VERSION 5.7 ;
  NOWIREEXTENSIONATPIN ON ;
  DIVIDERCHAR "/" ;
  BUSBITCHARS "[]" ;
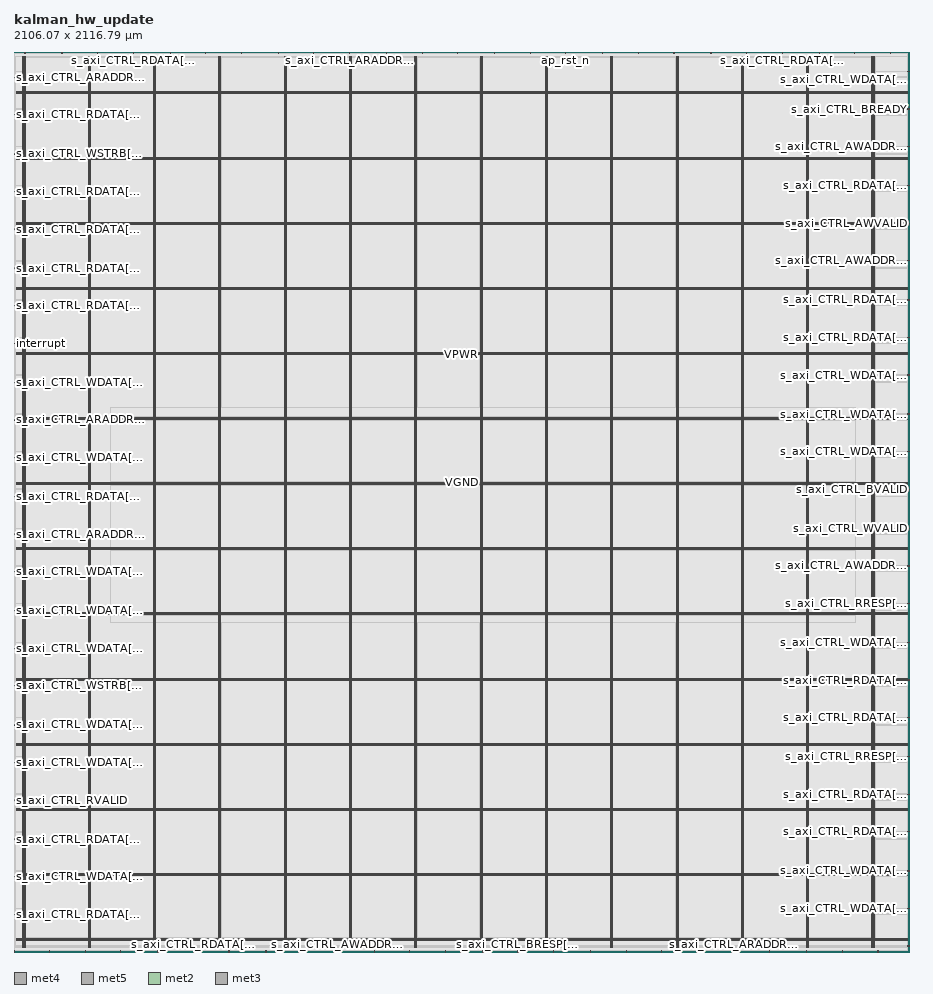
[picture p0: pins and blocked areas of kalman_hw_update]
MACRO kalman_hw_update
  CLASS BLOCK ;
  FOREIGN kalman_hw_update ;
  ORIGIN 0.000 0.000 ;
  SIZE 2106.070 BY 2116.790 ;
  PIN VGND
    DIRECTION INOUT ;
    USE GROUND ;
    PORT
      LAYER met4 ;
        RECT 24.340 10.640 25.940 2105.520 ;
    END
    PORT
      LAYER met4 ;
        RECT 177.940 10.640 179.540 2105.520 ;
    END
    PORT
      LAYER met4 ;
        RECT 331.540 10.640 333.140 2105.520 ;
    END
    PORT
      LAYER met4 ;
        RECT 485.140 10.640 486.740 2105.520 ;
    END
    PORT
      LAYER met4 ;
        RECT 638.740 10.640 640.340 2105.520 ;
    END
    PORT
      LAYER met4 ;
        RECT 792.340 10.640 793.940 2105.520 ;
    END
    PORT
      LAYER met4 ;
        RECT 945.940 10.640 947.540 2105.520 ;
    END
    PORT
      LAYER met4 ;
        RECT 1099.540 10.640 1101.140 2105.520 ;
    END
    PORT
      LAYER met4 ;
        RECT 1253.140 10.640 1254.740 2105.520 ;
    END
    PORT
      LAYER met4 ;
        RECT 1406.740 10.640 1408.340 2105.520 ;
    END
    PORT
      LAYER met4 ;
        RECT 1560.340 10.640 1561.940 2105.520 ;
    END
    PORT
      LAYER met4 ;
        RECT 1713.940 10.640 1715.540 2105.520 ;
    END
    PORT
      LAYER met4 ;
        RECT 1867.540 10.640 1869.140 2105.520 ;
    END
    PORT
      LAYER met4 ;
        RECT 2021.140 10.640 2022.740 2105.520 ;
    END
    PORT
      LAYER met5 ;
        RECT 5.280 30.030 2100.600 31.630 ;
    END
    PORT
      LAYER met5 ;
        RECT 5.280 183.210 2100.600 184.810 ;
    END
    PORT
      LAYER met5 ;
        RECT 5.280 336.390 2100.600 337.990 ;
    END
    PORT
      LAYER met5 ;
        RECT 5.280 489.570 2100.600 491.170 ;
    END
    PORT
      LAYER met5 ;
        RECT 5.280 642.750 2100.600 644.350 ;
    END
    PORT
      LAYER met5 ;
        RECT 5.280 795.930 2100.600 797.530 ;
    END
    PORT
      LAYER met5 ;
        RECT 5.280 949.110 2100.600 950.710 ;
    END
    PORT
      LAYER met5 ;
        RECT 5.280 1102.290 2100.600 1103.890 ;
    END
    PORT
      LAYER met5 ;
        RECT 5.280 1255.470 2100.600 1257.070 ;
    END
    PORT
      LAYER met5 ;
        RECT 5.280 1408.650 2100.600 1410.250 ;
    END
    PORT
      LAYER met5 ;
        RECT 5.280 1561.830 2100.600 1563.430 ;
    END
    PORT
      LAYER met5 ;
        RECT 5.280 1715.010 2100.600 1716.610 ;
    END
    PORT
      LAYER met5 ;
        RECT 5.280 1868.190 2100.600 1869.790 ;
    END
    PORT
      LAYER met5 ;
        RECT 5.280 2021.370 2100.600 2022.970 ;
    END
  END VGND
  PIN VPWR
    DIRECTION INOUT ;
    USE POWER ;
    PORT
      LAYER met4 ;
        RECT 21.040 10.640 22.640 2105.520 ;
    END
    PORT
      LAYER met4 ;
        RECT 174.640 10.640 176.240 2105.520 ;
    END
    PORT
      LAYER met4 ;
        RECT 328.240 10.640 329.840 2105.520 ;
    END
    PORT
      LAYER met4 ;
        RECT 481.840 10.640 483.440 2105.520 ;
    END
    PORT
      LAYER met4 ;
        RECT 635.440 10.640 637.040 2105.520 ;
    END
    PORT
      LAYER met4 ;
        RECT 789.040 10.640 790.640 2105.520 ;
    END
    PORT
      LAYER met4 ;
        RECT 942.640 10.640 944.240 2105.520 ;
    END
    PORT
      LAYER met4 ;
        RECT 1096.240 10.640 1097.840 2105.520 ;
    END
    PORT
      LAYER met4 ;
        RECT 1249.840 10.640 1251.440 2105.520 ;
    END
    PORT
      LAYER met4 ;
        RECT 1403.440 10.640 1405.040 2105.520 ;
    END
    PORT
      LAYER met4 ;
        RECT 1557.040 10.640 1558.640 2105.520 ;
    END
    PORT
      LAYER met4 ;
        RECT 1710.640 10.640 1712.240 2105.520 ;
    END
    PORT
      LAYER met4 ;
        RECT 1864.240 10.640 1865.840 2105.520 ;
    END
    PORT
      LAYER met4 ;
        RECT 2017.840 10.640 2019.440 2105.520 ;
    END
    PORT
      LAYER met5 ;
        RECT 5.280 26.730 2100.600 28.330 ;
    END
    PORT
      LAYER met5 ;
        RECT 5.280 179.910 2100.600 181.510 ;
    END
    PORT
      LAYER met5 ;
        RECT 5.280 333.090 2100.600 334.690 ;
    END
    PORT
      LAYER met5 ;
        RECT 5.280 486.270 2100.600 487.870 ;
    END
    PORT
      LAYER met5 ;
        RECT 5.280 639.450 2100.600 641.050 ;
    END
    PORT
      LAYER met5 ;
        RECT 5.280 792.630 2100.600 794.230 ;
    END
    PORT
      LAYER met5 ;
        RECT 5.280 945.810 2100.600 947.410 ;
    END
    PORT
      LAYER met5 ;
        RECT 5.280 1098.990 2100.600 1100.590 ;
    END
    PORT
      LAYER met5 ;
        RECT 5.280 1252.170 2100.600 1253.770 ;
    END
    PORT
      LAYER met5 ;
        RECT 5.280 1405.350 2100.600 1406.950 ;
    END
    PORT
      LAYER met5 ;
        RECT 5.280 1558.530 2100.600 1560.130 ;
    END
    PORT
      LAYER met5 ;
        RECT 5.280 1711.710 2100.600 1713.310 ;
    END
    PORT
      LAYER met5 ;
        RECT 5.280 1864.890 2100.600 1866.490 ;
    END
    PORT
      LAYER met5 ;
        RECT 5.280 2018.070 2100.600 2019.670 ;
    END
  END VPWR
  PIN ap_clk
    DIRECTION INPUT ;
    USE SIGNAL ;
    ANTENNAGATEAREA 1.286700 ;
    ANTENNADIFFAREA 0.434700 ;
    PORT
      LAYER met2 ;
        RECT 875.930 2112.790 876.210 2116.790 ;
    END
  END ap_clk
  PIN ap_rst_n
    DIRECTION INPUT ;
    USE SIGNAL ;
    ANTENNAGATEAREA 0.126000 ;
    PORT
      LAYER met2 ;
        RECT 1297.750 2112.790 1298.030 2116.790 ;
    END
  END ap_rst_n
  PIN interrupt
    DIRECTION OUTPUT TRISTATE ;
    USE SIGNAL ;
    ANTENNADIFFAREA 0.795200 ;
    PORT
      LAYER met3 ;
        RECT 0.000 1431.440 4.000 1432.040 ;
    END
  END interrupt
  PIN s_axi_CTRL_ARADDR[0]
    DIRECTION INPUT ;
    USE SIGNAL ;
    ANTENNAGATEAREA 0.126000 ;
    PORT
      LAYER met3 ;
        RECT 0.000 2057.040 4.000 2057.640 ;
    END
  END s_axi_CTRL_ARADDR[0]
  PIN s_axi_CTRL_ARADDR[1]
    DIRECTION INPUT ;
    USE SIGNAL ;
    ANTENNAGATEAREA 0.990000 ;
    PORT
      LAYER met2 ;
        RECT 1693.810 0.000 1694.090 4.000 ;
    END
  END s_axi_CTRL_ARADDR[1]
  PIN s_axi_CTRL_ARADDR[2]
    DIRECTION INPUT ;
    USE SIGNAL ;
    ANTENNAGATEAREA 0.126000 ;
    PORT
      LAYER met2 ;
        RECT 505.630 0.000 505.910 4.000 ;
    END
  END s_axi_CTRL_ARADDR[2]
  PIN s_axi_CTRL_ARADDR[3]
    DIRECTION INPUT ;
    USE SIGNAL ;
    ANTENNAGATEAREA 0.126000 ;
    PORT
      LAYER met2 ;
        RECT 788.990 2112.790 789.270 2116.790 ;
    END
  END s_axi_CTRL_ARADDR[3]
  PIN s_axi_CTRL_ARADDR[4]
    DIRECTION INPUT ;
    USE SIGNAL ;
    ANTENNAGATEAREA 0.126000 ;
    PORT
      LAYER met3 ;
        RECT 0.000 1251.240 4.000 1251.840 ;
    END
  END s_axi_CTRL_ARADDR[4]
  PIN s_axi_CTRL_ARADDR[5]
    DIRECTION INPUT ;
    USE SIGNAL ;
    ANTENNAGATEAREA 0.126000 ;
    PORT
      LAYER met3 ;
        RECT 0.000 982.640 4.000 983.240 ;
    END
  END s_axi_CTRL_ARADDR[5]
  PIN s_axi_CTRL_ARREADY
    DIRECTION OUTPUT TRISTATE ;
    USE SIGNAL ;
    ANTENNADIFFAREA 0.795200 ;
    PORT
      LAYER met2 ;
        RECT 251.250 0.000 251.530 4.000 ;
    END
  END s_axi_CTRL_ARREADY
  PIN s_axi_CTRL_ARVALID
    DIRECTION INPUT ;
    USE SIGNAL ;
    ANTENNAGATEAREA 0.126000 ;
    PORT
      LAYER met3 ;
        RECT 2102.070 13.640 2106.070 14.240 ;
    END
  END s_axi_CTRL_ARVALID
  PIN s_axi_CTRL_AWADDR[0]
    DIRECTION INPUT ;
    USE SIGNAL ;
    ANTENNAGATEAREA 0.126000 ;
    PORT
      LAYER met3 ;
        RECT 2102.070 1625.240 2106.070 1625.840 ;
    END
  END s_axi_CTRL_AWADDR[0]
  PIN s_axi_CTRL_AWADDR[1]
    DIRECTION INPUT ;
    USE SIGNAL ;
    ANTENNAGATEAREA 0.126000 ;
    PORT
      LAYER met2 ;
        RECT 1948.190 0.000 1948.470 4.000 ;
    END
  END s_axi_CTRL_AWADDR[1]
  PIN s_axi_CTRL_AWADDR[2]
    DIRECTION INPUT ;
    USE SIGNAL ;
    ANTENNAGATEAREA 0.126000 ;
    PORT
      LAYER met2 ;
        RECT 2060.890 2112.790 2061.170 2116.790 ;
    END
  END s_axi_CTRL_AWADDR[2]
  PIN s_axi_CTRL_AWADDR[3]
    DIRECTION INPUT ;
    USE SIGNAL ;
    ANTENNAGATEAREA 0.126000 ;
    PORT
      LAYER met3 ;
        RECT 2102.070 907.840 2106.070 908.440 ;
    END
  END s_axi_CTRL_AWADDR[3]
  PIN s_axi_CTRL_AWADDR[4]
    DIRECTION INPUT ;
    USE SIGNAL ;
    ANTENNAGATEAREA 0.126000 ;
    PORT
      LAYER met2 ;
        RECT 760.010 0.000 760.290 4.000 ;
    END
  END s_axi_CTRL_AWADDR[4]
  PIN s_axi_CTRL_AWADDR[5]
    DIRECTION INPUT ;
    USE SIGNAL ;
    ANTENNAGATEAREA 0.126000 ;
    PORT
      LAYER met3 ;
        RECT 2102.070 1893.840 2106.070 1894.440 ;
    END
  END s_axi_CTRL_AWADDR[5]
  PIN s_axi_CTRL_AWREADY
    DIRECTION OUTPUT TRISTATE ;
    USE SIGNAL ;
    ANTENNADIFFAREA 0.795200 ;
    PORT
      LAYER met2 ;
        RECT 621.550 2112.790 621.830 2116.790 ;
    END
  END s_axi_CTRL_AWREADY
  PIN s_axi_CTRL_AWVALID
    DIRECTION INPUT ;
    USE SIGNAL ;
    ANTENNAGATEAREA 0.126000 ;
    PORT
      LAYER met3 ;
        RECT 2102.070 1713.640 2106.070 1714.240 ;
    END
  END s_axi_CTRL_AWVALID
  PIN s_axi_CTRL_BREADY
    DIRECTION INPUT ;
    USE SIGNAL ;
    ANTENNAGATEAREA 0.126000 ;
    PORT
      LAYER met3 ;
        RECT 2102.070 1982.240 2106.070 1982.840 ;
    END
  END s_axi_CTRL_BREADY
  PIN s_axi_CTRL_BRESP[0]
    DIRECTION OUTPUT TRISTATE ;
    USE SIGNAL ;
    PORT
      LAYER met2 ;
        RECT 1185.050 0.000 1185.330 4.000 ;
    END
  END s_axi_CTRL_BRESP[0]
  PIN s_axi_CTRL_BRESP[1]
    DIRECTION OUTPUT TRISTATE ;
    USE SIGNAL ;
    PORT
      LAYER met2 ;
        RECT 1468.410 2112.790 1468.690 2116.790 ;
    END
  END s_axi_CTRL_BRESP[1]
  PIN s_axi_CTRL_BVALID
    DIRECTION OUTPUT TRISTATE ;
    USE SIGNAL ;
    ANTENNADIFFAREA 0.445500 ;
    PORT
      LAYER met3 ;
        RECT 2102.070 1088.040 2106.070 1088.640 ;
    END
  END s_axi_CTRL_BVALID
  PIN s_axi_CTRL_RDATA[0]
    DIRECTION OUTPUT TRISTATE ;
    USE SIGNAL ;
    ANTENNADIFFAREA 0.795200 ;
    PORT
      LAYER met3 ;
        RECT 2102.070 550.840 2106.070 551.440 ;
    END
  END s_axi_CTRL_RDATA[0]
  PIN s_axi_CTRL_RDATA[10]
    DIRECTION OUTPUT TRISTATE ;
    USE SIGNAL ;
    ANTENNADIFFAREA 0.795200 ;
    PORT
      LAYER met3 ;
        RECT 0.000 265.240 4.000 265.840 ;
    END
  END s_axi_CTRL_RDATA[10]
  PIN s_axi_CTRL_RDATA[11]
    DIRECTION OUTPUT TRISTATE ;
    USE SIGNAL ;
    ANTENNADIFFAREA 0.795200 ;
    PORT
      LAYER met2 ;
        RECT 846.950 0.000 847.230 4.000 ;
    END
  END s_axi_CTRL_RDATA[11]
  PIN s_axi_CTRL_RDATA[12]
    DIRECTION OUTPUT TRISTATE ;
    USE SIGNAL ;
    ANTENNADIFFAREA 0.795200 ;
    PORT
      LAYER met2 ;
        RECT 1777.530 0.000 1777.810 4.000 ;
    END
  END s_axi_CTRL_RDATA[12]
  PIN s_axi_CTRL_RDATA[13]
    DIRECTION OUTPUT TRISTATE ;
    USE SIGNAL ;
    ANTENNADIFFAREA 0.795200 ;
    PORT
      LAYER met2 ;
        RECT 959.650 2112.790 959.930 2116.790 ;
    END
  END s_axi_CTRL_RDATA[13]
  PIN s_axi_CTRL_RDATA[14]
    DIRECTION OUTPUT TRISTATE ;
    USE SIGNAL ;
    ANTENNADIFFAREA 0.795200 ;
    PORT
      LAYER met2 ;
        RECT 1384.690 2112.790 1384.970 2116.790 ;
    END
  END s_axi_CTRL_RDATA[14]
  PIN s_axi_CTRL_RDATA[15]
    DIRECTION OUTPUT TRISTATE ;
    USE SIGNAL ;
    ANTENNADIFFAREA 0.445500 ;
    PORT
      LAYER met3 ;
        RECT 2102.070 1802.040 2106.070 1802.640 ;
    END
  END s_axi_CTRL_RDATA[15]
  PIN s_axi_CTRL_RDATA[16]
    DIRECTION OUTPUT TRISTATE ;
    USE SIGNAL ;
    ANTENNADIFFAREA 0.445500 ;
    PORT
      LAYER met3 ;
        RECT 2102.070 370.640 2106.070 371.240 ;
    END
  END s_axi_CTRL_RDATA[16]
  PIN s_axi_CTRL_RDATA[17]
    DIRECTION OUTPUT TRISTATE ;
    USE SIGNAL ;
    ANTENNADIFFAREA 0.795200 ;
    PORT
      LAYER met2 ;
        RECT 1043.370 2112.790 1043.650 2116.790 ;
    END
  END s_axi_CTRL_RDATA[17]
  PIN s_axi_CTRL_RDATA[18]
    DIRECTION OUTPUT TRISTATE ;
    USE SIGNAL ;
    ANTENNADIFFAREA 0.795200 ;
    PORT
      LAYER met2 ;
        RECT 25.850 2112.790 26.130 2116.790 ;
    END
  END s_axi_CTRL_RDATA[18]
  PIN s_axi_CTRL_RDATA[19]
    DIRECTION OUTPUT TRISTATE ;
    USE SIGNAL ;
    ANTENNADIFFAREA 0.795200 ;
    PORT
      LAYER met2 ;
        RECT 1806.510 2112.790 1806.790 2116.790 ;
    END
  END s_axi_CTRL_RDATA[19]
  PIN s_axi_CTRL_RDATA[1]
    DIRECTION OUTPUT TRISTATE ;
    USE SIGNAL ;
    ANTENNADIFFAREA 0.795200 ;
    PORT
      LAYER met2 ;
        RECT 421.910 0.000 422.190 4.000 ;
    END
  END s_axi_CTRL_RDATA[1]
  PIN s_axi_CTRL_RDATA[20]
    DIRECTION OUTPUT TRISTATE ;
    USE SIGNAL ;
    ANTENNADIFFAREA 0.795200 ;
    PORT
      LAYER met2 ;
        RECT 705.270 2112.790 705.550 2116.790 ;
    END
  END s_axi_CTRL_RDATA[20]
  PIN s_axi_CTRL_RDATA[21]
    DIRECTION OUTPUT TRISTATE ;
    USE SIGNAL ;
    ANTENNADIFFAREA 0.445500 ;
    PORT
      LAYER met3 ;
        RECT 2102.070 1533.440 2106.070 1534.040 ;
    END
  END s_axi_CTRL_RDATA[21]
  PIN s_axi_CTRL_RDATA[22]
    DIRECTION OUTPUT TRISTATE ;
    USE SIGNAL ;
    ANTENNADIFFAREA 0.445500 ;
    PORT
      LAYER met3 ;
        RECT 2102.070 639.240 2106.070 639.840 ;
    END
  END s_axi_CTRL_RDATA[22]
  PIN s_axi_CTRL_RDATA[23]
    DIRECTION OUTPUT TRISTATE ;
    USE SIGNAL ;
    ANTENNADIFFAREA 0.795200 ;
    PORT
      LAYER met2 ;
        RECT 1214.030 2112.790 1214.310 2116.790 ;
    END
  END s_axi_CTRL_RDATA[23]
  PIN s_axi_CTRL_RDATA[24]
    DIRECTION OUTPUT TRISTATE ;
    USE SIGNAL ;
    ANTENNADIFFAREA 0.795200 ;
    PORT
      LAYER met2 ;
        RECT 1893.450 2112.790 1893.730 2116.790 ;
    END
  END s_axi_CTRL_RDATA[24]
  PIN s_axi_CTRL_RDATA[25]
    DIRECTION OUTPUT TRISTATE ;
    USE SIGNAL ;
    ANTENNADIFFAREA 0.795200 ;
    PORT
      LAYER met2 ;
        RECT 2031.910 0.000 2032.190 4.000 ;
    END
  END s_axi_CTRL_RDATA[25]
  PIN s_axi_CTRL_RDATA[26]
    DIRECTION OUTPUT TRISTATE ;
    USE SIGNAL ;
    ANTENNADIFFAREA 0.445500 ;
    PORT
      LAYER met3 ;
        RECT 2102.070 1445.040 2106.070 1445.640 ;
    END
  END s_axi_CTRL_RDATA[26]
  PIN s_axi_CTRL_RDATA[27]
    DIRECTION OUTPUT TRISTATE ;
    USE SIGNAL ;
    ANTENNADIFFAREA 0.795200 ;
    PORT
      LAYER met3 ;
        RECT 0.000 1519.840 4.000 1520.440 ;
    END
  END s_axi_CTRL_RDATA[27]
  PIN s_axi_CTRL_RDATA[28]
    DIRECTION OUTPUT TRISTATE ;
    USE SIGNAL ;
    ANTENNADIFFAREA 0.795200 ;
    PORT
      LAYER met2 ;
        RECT 1355.710 0.000 1355.990 4.000 ;
    END
  END s_axi_CTRL_RDATA[28]
  PIN s_axi_CTRL_RDATA[29]
    DIRECTION OUTPUT TRISTATE ;
    USE SIGNAL ;
    ANTENNADIFFAREA 0.795200 ;
    PORT
      LAYER met3 ;
        RECT 0.000 1071.040 4.000 1071.640 ;
    END
  END s_axi_CTRL_RDATA[29]
  PIN s_axi_CTRL_RDATA[2]
    DIRECTION OUTPUT TRISTATE ;
    USE SIGNAL ;
    ANTENNADIFFAREA 0.795200 ;
    PORT
      LAYER met3 ;
        RECT 2102.070 282.240 2106.070 282.840 ;
    END
  END s_axi_CTRL_RDATA[2]
  PIN s_axi_CTRL_RDATA[30]
    DIRECTION OUTPUT TRISTATE ;
    USE SIGNAL ;
    ANTENNADIFFAREA 0.795200 ;
    PORT
      LAYER met3 ;
        RECT 0.000 88.440 4.000 89.040 ;
    END
  END s_axi_CTRL_RDATA[30]
  PIN s_axi_CTRL_RDATA[31]
    DIRECTION OUTPUT TRISTATE ;
    USE SIGNAL ;
    ANTENNADIFFAREA 0.795200 ;
    PORT
      LAYER met3 ;
        RECT 0.000 1968.640 4.000 1969.240 ;
    END
  END s_axi_CTRL_RDATA[31]
  PIN s_axi_CTRL_RDATA[3]
    DIRECTION OUTPUT TRISTATE ;
    USE SIGNAL ;
    ANTENNADIFFAREA 0.795200 ;
    PORT
      LAYER met3 ;
        RECT 0.000 1700.040 4.000 1700.640 ;
    END
  END s_axi_CTRL_RDATA[3]
  PIN s_axi_CTRL_RDATA[4]
    DIRECTION OUTPUT TRISTATE ;
    USE SIGNAL ;
    ANTENNADIFFAREA 0.795200 ;
    PORT
      LAYER met3 ;
        RECT 0.000 1608.240 4.000 1608.840 ;
    END
  END s_axi_CTRL_RDATA[4]
  PIN s_axi_CTRL_RDATA[5]
    DIRECTION OUTPUT TRISTATE ;
    USE SIGNAL ;
    ANTENNADIFFAREA 0.795200 ;
    PORT
      LAYER met2 ;
        RECT 1523.150 0.000 1523.430 4.000 ;
    END
  END s_axi_CTRL_RDATA[5]
  PIN s_axi_CTRL_RDATA[6]
    DIRECTION OUTPUT TRISTATE ;
    USE SIGNAL ;
    ANTENNADIFFAREA 0.795200 ;
    PORT
      LAYER met3 ;
        RECT 0.000 1788.440 4.000 1789.040 ;
    END
  END s_axi_CTRL_RDATA[6]
  PIN s_axi_CTRL_RDATA[7]
    DIRECTION OUTPUT TRISTATE ;
    USE SIGNAL ;
    ANTENNADIFFAREA 0.795200 ;
    PORT
      LAYER met2 ;
        RECT 280.230 2112.790 280.510 2116.790 ;
    END
  END s_axi_CTRL_RDATA[7]
  PIN s_axi_CTRL_RDATA[8]
    DIRECTION OUTPUT TRISTATE ;
    USE SIGNAL ;
    ANTENNADIFFAREA 0.795200 ;
    PORT
      LAYER met2 ;
        RECT 167.530 0.000 167.810 4.000 ;
    END
  END s_axi_CTRL_RDATA[8]
  PIN s_axi_CTRL_RDATA[9]
    DIRECTION OUTPUT TRISTATE ;
    USE SIGNAL ;
    ANTENNADIFFAREA 0.795200 ;
    PORT
      LAYER met2 ;
        RECT 592.570 0.000 592.850 4.000 ;
    END
  END s_axi_CTRL_RDATA[9]
  PIN s_axi_CTRL_RREADY
    DIRECTION INPUT ;
    USE SIGNAL ;
    ANTENNAGATEAREA 0.126000 ;
    PORT
      LAYER met2 ;
        RECT 1864.470 0.000 1864.750 4.000 ;
    END
  END s_axi_CTRL_RREADY
  PIN s_axi_CTRL_RRESP[0]
    DIRECTION OUTPUT TRISTATE ;
    USE SIGNAL ;
    PORT
      LAYER met3 ;
        RECT 2102.070 819.440 2106.070 820.040 ;
    END
  END s_axi_CTRL_RRESP[0]
  PIN s_axi_CTRL_RRESP[1]
    DIRECTION OUTPUT TRISTATE ;
    USE SIGNAL ;
    PORT
      LAYER met3 ;
        RECT 2102.070 459.040 2106.070 459.640 ;
    END
  END s_axi_CTRL_RRESP[1]
  PIN s_axi_CTRL_RVALID
    DIRECTION OUTPUT TRISTATE ;
    USE SIGNAL ;
    ANTENNADIFFAREA 0.795200 ;
    PORT
      LAYER met3 ;
        RECT 0.000 357.040 4.000 357.640 ;
    END
  END s_axi_CTRL_RVALID
  PIN s_axi_CTRL_WDATA[0]
    DIRECTION INPUT ;
    USE SIGNAL ;
    ANTENNAGATEAREA 0.126000 ;
    PORT
      LAYER met3 ;
        RECT 0.000 176.840 4.000 177.440 ;
    END
  END s_axi_CTRL_WDATA[0]
  PIN s_axi_CTRL_WDATA[10]
    DIRECTION INPUT ;
    USE SIGNAL ;
    ANTENNAGATEAREA 0.126000 ;
    PORT
      LAYER met3 ;
        RECT 2102.070 102.040 2106.070 102.640 ;
    END
  END s_axi_CTRL_WDATA[10]
  PIN s_axi_CTRL_WDATA[11]
    DIRECTION INPUT ;
    USE SIGNAL ;
    ANTENNAGATEAREA 0.126000 ;
    PORT
      LAYER met2 ;
        RECT 367.170 2112.790 367.450 2116.790 ;
    END
  END s_axi_CTRL_WDATA[11]
  PIN s_axi_CTRL_WDATA[12]
    DIRECTION INPUT ;
    USE SIGNAL ;
    ANTENNAGATEAREA 0.126000 ;
    PORT
      LAYER met3 ;
        RECT 2102.070 727.640 2106.070 728.240 ;
    END
  END s_axi_CTRL_WDATA[12]
  PIN s_axi_CTRL_WDATA[13]
    DIRECTION INPUT ;
    USE SIGNAL ;
    ANTENNAGATEAREA 0.126000 ;
    PORT
      LAYER met3 ;
        RECT 0.000 894.240 4.000 894.840 ;
    END
  END s_axi_CTRL_WDATA[13]
  PIN s_axi_CTRL_WDATA[14]
    DIRECTION INPUT ;
    USE SIGNAL ;
    ANTENNAGATEAREA 0.126000 ;
    PORT
      LAYER met2 ;
        RECT 1610.090 0.000 1610.370 4.000 ;
    END
  END s_axi_CTRL_WDATA[14]
  PIN s_axi_CTRL_WDATA[15]
    DIRECTION INPUT ;
    USE SIGNAL ;
    ANTENNAGATEAREA 0.126000 ;
    PORT
      LAYER met3 ;
        RECT 2102.070 1356.640 2106.070 1357.240 ;
    END
  END s_axi_CTRL_WDATA[15]
  PIN s_axi_CTRL_WDATA[16]
    DIRECTION INPUT ;
    USE SIGNAL ;
    ANTENNAGATEAREA 0.126000 ;
    PORT
      LAYER met3 ;
        RECT 0.000 445.440 4.000 446.040 ;
    END
  END s_axi_CTRL_WDATA[16]
  PIN s_axi_CTRL_WDATA[17]
    DIRECTION INPUT ;
    USE SIGNAL ;
    ANTENNAGATEAREA 0.126000 ;
    PORT
      LAYER met3 ;
        RECT 0.000 1339.640 4.000 1340.240 ;
    END
  END s_axi_CTRL_WDATA[17]
  PIN s_axi_CTRL_WDATA[18]
    DIRECTION INPUT ;
    USE SIGNAL ;
    ANTENNAGATEAREA 0.126000 ;
    PORT
      LAYER met2 ;
        RECT 1014.390 0.000 1014.670 4.000 ;
    END
  END s_axi_CTRL_WDATA[18]
  PIN s_axi_CTRL_WDATA[19]
    DIRECTION INPUT ;
    USE SIGNAL ;
    ANTENNAGATEAREA 0.126000 ;
    PORT
      LAYER met2 ;
        RECT 0.090 0.000 0.370 4.000 ;
    END
  END s_axi_CTRL_WDATA[19]
  PIN s_axi_CTRL_WDATA[1]
    DIRECTION INPUT ;
    USE SIGNAL ;
    ANTENNAGATEAREA 0.126000 ;
    PORT
      LAYER met2 ;
        RECT 1268.770 0.000 1269.050 4.000 ;
    END
  END s_axi_CTRL_WDATA[1]
  PIN s_axi_CTRL_WDATA[20]
    DIRECTION INPUT ;
    USE SIGNAL ;
    ANTENNAGATEAREA 0.126000 ;
    PORT
      LAYER met2 ;
        RECT 534.610 2112.790 534.890 2116.790 ;
    END
  END s_axi_CTRL_WDATA[20]
  PIN s_axi_CTRL_WDATA[21]
    DIRECTION INPUT ;
    USE SIGNAL ;
    ANTENNAGATEAREA 0.126000 ;
    PORT
      LAYER met2 ;
        RECT 1130.310 2112.790 1130.590 2116.790 ;
    END
  END s_axi_CTRL_WDATA[21]
  PIN s_axi_CTRL_WDATA[22]
    DIRECTION INPUT ;
    USE SIGNAL ;
    ANTENNAGATEAREA 0.126000 ;
    PORT
      LAYER met3 ;
        RECT 0.000 714.040 4.000 714.640 ;
    END
  END s_axi_CTRL_WDATA[22]
  PIN s_axi_CTRL_WDATA[23]
    DIRECTION INPUT ;
    USE SIGNAL ;
    ANTENNAGATEAREA 0.126000 ;
    PORT
      LAYER met2 ;
        RECT 112.790 2112.790 113.070 2116.790 ;
    END
  END s_axi_CTRL_WDATA[23]
  PIN s_axi_CTRL_WDATA[24]
    DIRECTION INPUT ;
    USE SIGNAL ;
    ANTENNAGATEAREA 0.126000 ;
    PORT
      LAYER met3 ;
        RECT 0.000 1162.840 4.000 1163.440 ;
    END
  END s_axi_CTRL_WDATA[24]
  PIN s_axi_CTRL_WDATA[25]
    DIRECTION INPUT ;
    USE SIGNAL ;
    ANTENNAGATEAREA 0.126000 ;
    PORT
      LAYER met2 ;
        RECT 83.810 0.000 84.090 4.000 ;
    END
  END s_axi_CTRL_WDATA[25]
  PIN s_axi_CTRL_WDATA[26]
    DIRECTION INPUT ;
    USE SIGNAL ;
    ANTENNAGATEAREA 0.126000 ;
    PORT
      LAYER met2 ;
        RECT 1977.170 2112.790 1977.450 2116.790 ;
    END
  END s_axi_CTRL_WDATA[26]
  PIN s_axi_CTRL_WDATA[27]
    DIRECTION INPUT ;
    USE SIGNAL ;
    ANTENNAGATEAREA 0.126000 ;
    PORT
      LAYER met2 ;
        RECT 1552.130 2112.790 1552.410 2116.790 ;
    END
  END s_axi_CTRL_WDATA[27]
  PIN s_axi_CTRL_WDATA[28]
    DIRECTION INPUT ;
    USE SIGNAL ;
    ANTENNAGATEAREA 0.126000 ;
    PORT
      LAYER met2 ;
        RECT 930.670 0.000 930.950 4.000 ;
    END
  END s_axi_CTRL_WDATA[28]
  PIN s_axi_CTRL_WDATA[29]
    DIRECTION INPUT ;
    USE SIGNAL ;
    ANTENNAGATEAREA 0.990000 ;
    PORT
      LAYER met3 ;
        RECT 2102.070 2070.640 2106.070 2071.240 ;
    END
  END s_axi_CTRL_WDATA[29]
  PIN s_axi_CTRL_WDATA[2]
    DIRECTION INPUT ;
    USE SIGNAL ;
    ANTENNAGATEAREA 0.126000 ;
    PORT
      LAYER met3 ;
        RECT 2102.070 190.440 2106.070 191.040 ;
    END
  END s_axi_CTRL_WDATA[2]
  PIN s_axi_CTRL_WDATA[30]
    DIRECTION INPUT ;
    USE SIGNAL ;
    ANTENNAGATEAREA 0.126000 ;
    PORT
      LAYER met3 ;
        RECT 0.000 533.840 4.000 534.440 ;
    END
  END s_axi_CTRL_WDATA[30]
  PIN s_axi_CTRL_WDATA[31]
    DIRECTION INPUT ;
    USE SIGNAL ;
    ANTENNAGATEAREA 0.126000 ;
    PORT
      LAYER met3 ;
        RECT 2102.070 1176.440 2106.070 1177.040 ;
    END
  END s_axi_CTRL_WDATA[31]
  PIN s_axi_CTRL_WDATA[3]
    DIRECTION INPUT ;
    USE SIGNAL ;
    ANTENNAGATEAREA 0.126000 ;
    PORT
      LAYER met2 ;
        RECT 338.190 0.000 338.470 4.000 ;
    END
  END s_axi_CTRL_WDATA[3]
  PIN s_axi_CTRL_WDATA[4]
    DIRECTION INPUT ;
    USE SIGNAL ;
    ANTENNAGATEAREA 0.126000 ;
    PORT
      LAYER met2 ;
        RECT 676.290 0.000 676.570 4.000 ;
    END
  END s_axi_CTRL_WDATA[4]
  PIN s_axi_CTRL_WDATA[5]
    DIRECTION INPUT ;
    USE SIGNAL ;
    ANTENNAGATEAREA 0.126000 ;
    PORT
      LAYER met3 ;
        RECT 0.000 802.440 4.000 803.040 ;
    END
  END s_axi_CTRL_WDATA[5]
  PIN s_axi_CTRL_WDATA[6]
    DIRECTION INPUT ;
    USE SIGNAL ;
    ANTENNAGATEAREA 0.126000 ;
    PORT
      LAYER met3 ;
        RECT 2102.070 1264.840 2106.070 1265.440 ;
    END
  END s_axi_CTRL_WDATA[6]
  PIN s_axi_CTRL_WDATA[7]
    DIRECTION INPUT ;
    USE SIGNAL ;
    ANTENNAGATEAREA 0.126000 ;
    PORT
      LAYER met2 ;
        RECT 1101.330 0.000 1101.610 4.000 ;
    END
  END s_axi_CTRL_WDATA[7]
  PIN s_axi_CTRL_WDATA[8]
    DIRECTION INPUT ;
    USE SIGNAL ;
    ANTENNAGATEAREA 0.990000 ;
    PORT
      LAYER met2 ;
        RECT 1722.790 2112.790 1723.070 2116.790 ;
    END
  END s_axi_CTRL_WDATA[8]
  PIN s_axi_CTRL_WDATA[9]
    DIRECTION INPUT ;
    USE SIGNAL ;
    ANTENNAGATEAREA 0.126000 ;
    PORT
      LAYER met2 ;
        RECT 1639.070 2112.790 1639.350 2116.790 ;
    END
  END s_axi_CTRL_WDATA[9]
  PIN s_axi_CTRL_WREADY
    DIRECTION OUTPUT TRISTATE ;
    USE SIGNAL ;
    ANTENNADIFFAREA 0.795200 ;
    PORT
      LAYER met2 ;
        RECT 196.510 2112.790 196.790 2116.790 ;
    END
  END s_axi_CTRL_WREADY
  PIN s_axi_CTRL_WSTRB[0]
    DIRECTION INPUT ;
    USE SIGNAL ;
    ANTENNAGATEAREA 0.126000 ;
    PORT
      LAYER met2 ;
        RECT 450.890 2112.790 451.170 2116.790 ;
    END
  END s_axi_CTRL_WSTRB[0]
  PIN s_axi_CTRL_WSTRB[1]
    DIRECTION INPUT ;
    USE SIGNAL ;
    ANTENNAGATEAREA 0.126000 ;
    PORT
      LAYER met2 ;
        RECT 1439.430 0.000 1439.710 4.000 ;
    END
  END s_axi_CTRL_WSTRB[1]
  PIN s_axi_CTRL_WSTRB[2]
    DIRECTION INPUT ;
    USE SIGNAL ;
    ANTENNAGATEAREA 0.126000 ;
    PORT
      LAYER met3 ;
        RECT 0.000 625.640 4.000 626.240 ;
    END
  END s_axi_CTRL_WSTRB[2]
  PIN s_axi_CTRL_WSTRB[3]
    DIRECTION INPUT ;
    USE SIGNAL ;
    ANTENNAGATEAREA 0.126000 ;
    PORT
      LAYER met3 ;
        RECT 0.000 1876.840 4.000 1877.440 ;
    END
  END s_axi_CTRL_WSTRB[3]
  PIN s_axi_CTRL_WVALID
    DIRECTION INPUT ;
    USE SIGNAL ;
    ANTENNAGATEAREA 0.126000 ;
    PORT
      LAYER met3 ;
        RECT 2102.070 996.240 2106.070 996.840 ;
    END
  END s_axi_CTRL_WVALID
  OBS
      LAYER li1 ;
        RECT 5.520 10.795 2100.360 2105.365 ;
      LAYER met1 ;
        RECT 0.070 9.900 2100.750 2105.520 ;
      LAYER met2 ;
        RECT 0.100 2112.510 25.570 2112.790 ;
        RECT 26.410 2112.510 112.510 2112.790 ;
        RECT 113.350 2112.510 196.230 2112.790 ;
        RECT 197.070 2112.510 279.950 2112.790 ;
        RECT 280.790 2112.510 366.890 2112.790 ;
        RECT 367.730 2112.510 450.610 2112.790 ;
        RECT 451.450 2112.510 534.330 2112.790 ;
        RECT 535.170 2112.510 621.270 2112.790 ;
        RECT 622.110 2112.510 704.990 2112.790 ;
        RECT 705.830 2112.510 788.710 2112.790 ;
        RECT 789.550 2112.510 875.650 2112.790 ;
        RECT 876.490 2112.510 959.370 2112.790 ;
        RECT 960.210 2112.510 1043.090 2112.790 ;
        RECT 1043.930 2112.510 1130.030 2112.790 ;
        RECT 1130.870 2112.510 1213.750 2112.790 ;
        RECT 1214.590 2112.510 1297.470 2112.790 ;
        RECT 1298.310 2112.510 1384.410 2112.790 ;
        RECT 1385.250 2112.510 1468.130 2112.790 ;
        RECT 1468.970 2112.510 1551.850 2112.790 ;
        RECT 1552.690 2112.510 1638.790 2112.790 ;
        RECT 1639.630 2112.510 1722.510 2112.790 ;
        RECT 1723.350 2112.510 1806.230 2112.790 ;
        RECT 1807.070 2112.510 1893.170 2112.790 ;
        RECT 1894.010 2112.510 1976.890 2112.790 ;
        RECT 1977.730 2112.510 2060.610 2112.790 ;
        RECT 2061.450 2112.510 2100.730 2112.790 ;
        RECT 0.100 4.280 2100.730 2112.510 ;
        RECT 0.650 3.670 83.530 4.280 ;
        RECT 84.370 3.670 167.250 4.280 ;
        RECT 168.090 3.670 250.970 4.280 ;
        RECT 251.810 3.670 337.910 4.280 ;
        RECT 338.750 3.670 421.630 4.280 ;
        RECT 422.470 3.670 505.350 4.280 ;
        RECT 506.190 3.670 592.290 4.280 ;
        RECT 593.130 3.670 676.010 4.280 ;
        RECT 676.850 3.670 759.730 4.280 ;
        RECT 760.570 3.670 846.670 4.280 ;
        RECT 847.510 3.670 930.390 4.280 ;
        RECT 931.230 3.670 1014.110 4.280 ;
        RECT 1014.950 3.670 1101.050 4.280 ;
        RECT 1101.890 3.670 1184.770 4.280 ;
        RECT 1185.610 3.670 1268.490 4.280 ;
        RECT 1269.330 3.670 1355.430 4.280 ;
        RECT 1356.270 3.670 1439.150 4.280 ;
        RECT 1439.990 3.670 1522.870 4.280 ;
        RECT 1523.710 3.670 1609.810 4.280 ;
        RECT 1610.650 3.670 1693.530 4.280 ;
        RECT 1694.370 3.670 1777.250 4.280 ;
        RECT 1778.090 3.670 1864.190 4.280 ;
        RECT 1865.030 3.670 1947.910 4.280 ;
        RECT 1948.750 3.670 2031.630 4.280 ;
        RECT 2032.470 3.670 2100.730 4.280 ;
      LAYER met3 ;
        RECT 3.990 2071.640 2102.070 2105.445 ;
        RECT 3.990 2070.240 2101.670 2071.640 ;
        RECT 3.990 2058.040 2102.070 2070.240 ;
        RECT 4.400 2056.640 2102.070 2058.040 ;
        RECT 3.990 1983.240 2102.070 2056.640 ;
        RECT 3.990 1981.840 2101.670 1983.240 ;
        RECT 3.990 1969.640 2102.070 1981.840 ;
        RECT 4.400 1968.240 2102.070 1969.640 ;
        RECT 3.990 1894.840 2102.070 1968.240 ;
        RECT 3.990 1893.440 2101.670 1894.840 ;
        RECT 3.990 1877.840 2102.070 1893.440 ;
        RECT 4.400 1876.440 2102.070 1877.840 ;
        RECT 3.990 1803.040 2102.070 1876.440 ;
        RECT 3.990 1801.640 2101.670 1803.040 ;
        RECT 3.990 1789.440 2102.070 1801.640 ;
        RECT 4.400 1788.040 2102.070 1789.440 ;
        RECT 3.990 1714.640 2102.070 1788.040 ;
        RECT 3.990 1713.240 2101.670 1714.640 ;
        RECT 3.990 1701.040 2102.070 1713.240 ;
        RECT 4.400 1699.640 2102.070 1701.040 ;
        RECT 3.990 1626.240 2102.070 1699.640 ;
        RECT 3.990 1624.840 2101.670 1626.240 ;
        RECT 3.990 1609.240 2102.070 1624.840 ;
        RECT 4.400 1607.840 2102.070 1609.240 ;
        RECT 3.990 1534.440 2102.070 1607.840 ;
        RECT 3.990 1533.040 2101.670 1534.440 ;
        RECT 3.990 1520.840 2102.070 1533.040 ;
        RECT 4.400 1519.440 2102.070 1520.840 ;
        RECT 3.990 1446.040 2102.070 1519.440 ;
        RECT 3.990 1444.640 2101.670 1446.040 ;
        RECT 3.990 1432.440 2102.070 1444.640 ;
        RECT 4.400 1431.040 2102.070 1432.440 ;
        RECT 3.990 1357.640 2102.070 1431.040 ;
        RECT 3.990 1356.240 2101.670 1357.640 ;
        RECT 3.990 1340.640 2102.070 1356.240 ;
        RECT 4.400 1339.240 2102.070 1340.640 ;
        RECT 3.990 1265.840 2102.070 1339.240 ;
        RECT 3.990 1264.440 2101.670 1265.840 ;
        RECT 3.990 1252.240 2102.070 1264.440 ;
        RECT 4.400 1250.840 2102.070 1252.240 ;
        RECT 3.990 1177.440 2102.070 1250.840 ;
        RECT 3.990 1176.040 2101.670 1177.440 ;
        RECT 3.990 1163.840 2102.070 1176.040 ;
        RECT 4.400 1162.440 2102.070 1163.840 ;
        RECT 3.990 1089.040 2102.070 1162.440 ;
        RECT 3.990 1087.640 2101.670 1089.040 ;
        RECT 3.990 1072.040 2102.070 1087.640 ;
        RECT 4.400 1070.640 2102.070 1072.040 ;
        RECT 3.990 997.240 2102.070 1070.640 ;
        RECT 3.990 995.840 2101.670 997.240 ;
        RECT 3.990 983.640 2102.070 995.840 ;
        RECT 4.400 982.240 2102.070 983.640 ;
        RECT 3.990 908.840 2102.070 982.240 ;
        RECT 3.990 907.440 2101.670 908.840 ;
        RECT 3.990 895.240 2102.070 907.440 ;
        RECT 4.400 893.840 2102.070 895.240 ;
        RECT 3.990 820.440 2102.070 893.840 ;
        RECT 3.990 819.040 2101.670 820.440 ;
        RECT 3.990 803.440 2102.070 819.040 ;
        RECT 4.400 802.040 2102.070 803.440 ;
        RECT 3.990 728.640 2102.070 802.040 ;
        RECT 3.990 727.240 2101.670 728.640 ;
        RECT 3.990 715.040 2102.070 727.240 ;
        RECT 4.400 713.640 2102.070 715.040 ;
        RECT 3.990 640.240 2102.070 713.640 ;
        RECT 3.990 638.840 2101.670 640.240 ;
        RECT 3.990 626.640 2102.070 638.840 ;
        RECT 4.400 625.240 2102.070 626.640 ;
        RECT 3.990 551.840 2102.070 625.240 ;
        RECT 3.990 550.440 2101.670 551.840 ;
        RECT 3.990 534.840 2102.070 550.440 ;
        RECT 4.400 533.440 2102.070 534.840 ;
        RECT 3.990 460.040 2102.070 533.440 ;
        RECT 3.990 458.640 2101.670 460.040 ;
        RECT 3.990 446.440 2102.070 458.640 ;
        RECT 4.400 445.040 2102.070 446.440 ;
        RECT 3.990 371.640 2102.070 445.040 ;
        RECT 3.990 370.240 2101.670 371.640 ;
        RECT 3.990 358.040 2102.070 370.240 ;
        RECT 4.400 356.640 2102.070 358.040 ;
        RECT 3.990 283.240 2102.070 356.640 ;
        RECT 3.990 281.840 2101.670 283.240 ;
        RECT 3.990 266.240 2102.070 281.840 ;
        RECT 4.400 264.840 2102.070 266.240 ;
        RECT 3.990 191.440 2102.070 264.840 ;
        RECT 3.990 190.040 2101.670 191.440 ;
        RECT 3.990 177.840 2102.070 190.040 ;
        RECT 4.400 176.440 2102.070 177.840 ;
        RECT 3.990 103.040 2102.070 176.440 ;
        RECT 3.990 101.640 2101.670 103.040 ;
        RECT 3.990 89.440 2102.070 101.640 ;
        RECT 4.400 88.040 2102.070 89.440 ;
        RECT 3.990 14.640 2102.070 88.040 ;
        RECT 3.990 13.240 2101.670 14.640 ;
        RECT 3.990 10.715 2102.070 13.240 ;
      LAYER met4 ;
        RECT 19.615 34.175 20.640 2103.745 ;
        RECT 23.040 34.175 23.940 2103.745 ;
        RECT 26.340 34.175 174.240 2103.745 ;
        RECT 176.640 34.175 177.540 2103.745 ;
        RECT 179.940 34.175 327.840 2103.745 ;
        RECT 330.240 34.175 331.140 2103.745 ;
        RECT 333.540 34.175 481.440 2103.745 ;
        RECT 483.840 34.175 484.740 2103.745 ;
        RECT 487.140 34.175 635.040 2103.745 ;
        RECT 637.440 34.175 638.340 2103.745 ;
        RECT 640.740 34.175 788.640 2103.745 ;
        RECT 791.040 34.175 791.940 2103.745 ;
        RECT 794.340 34.175 942.240 2103.745 ;
        RECT 944.640 34.175 945.540 2103.745 ;
        RECT 947.940 34.175 1095.840 2103.745 ;
        RECT 1098.240 34.175 1099.140 2103.745 ;
        RECT 1101.540 34.175 1249.440 2103.745 ;
        RECT 1251.840 34.175 1252.740 2103.745 ;
        RECT 1255.140 34.175 1403.040 2103.745 ;
        RECT 1405.440 34.175 1406.340 2103.745 ;
        RECT 1408.740 34.175 1556.640 2103.745 ;
        RECT 1559.040 34.175 1559.940 2103.745 ;
        RECT 1562.340 34.175 1710.240 2103.745 ;
        RECT 1712.640 34.175 1713.540 2103.745 ;
        RECT 1715.940 34.175 1863.840 2103.745 ;
        RECT 1866.240 34.175 1867.140 2103.745 ;
        RECT 1869.540 34.175 2017.440 2103.745 ;
        RECT 2019.840 34.175 2020.740 2103.745 ;
        RECT 2023.140 34.175 2026.465 2103.745 ;
      LAYER met5 ;
        RECT 226.900 1258.670 1978.340 1280.900 ;
        RECT 226.900 1105.490 1978.340 1250.570 ;
        RECT 226.900 952.310 1978.340 1097.390 ;
        RECT 226.900 799.130 1978.340 944.210 ;
        RECT 226.900 776.100 1978.340 791.030 ;
  END
END kalman_hw_update
END LIBRARY

